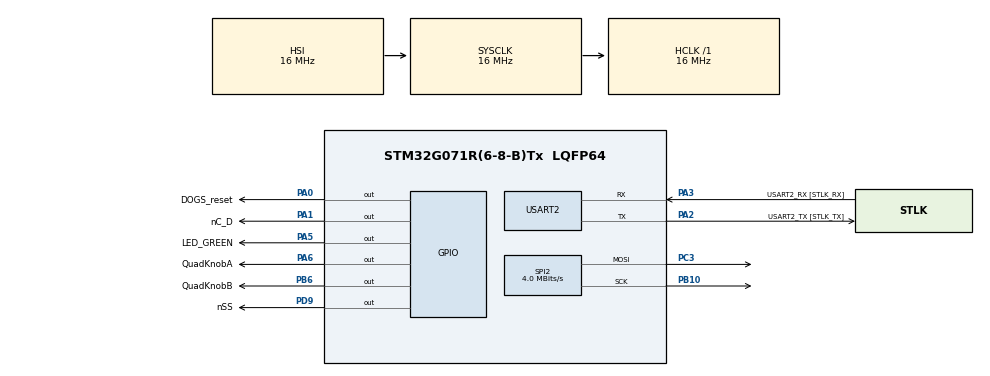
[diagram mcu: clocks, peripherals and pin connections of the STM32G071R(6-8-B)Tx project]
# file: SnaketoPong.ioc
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Mcu.Family=STM32G0
Mcu.Name=STM32G071R(6-8-B)Tx
Mcu.Package=LQFP64
NVIC.TIM17_IRQn=true\:0\:0\:false\:false\:true\:true\:true\:true
PA0.GPIO_Label=DOGS_reset
PA0.Signal=GPIO_Output
PA1.GPIO_Label=nC_D
PA1.Signal=GPIO_Output
PA13.GPIO_Label=TMS
PA13.Mode=Serial_Wire
PA13.Signal=SYS_SWDIO
PA14-BOOT0.GPIO_Label=TCK
PA14-BOOT0.Mode=Serial_Wire
PA14-BOOT0.Signal=SYS_SWCLK
PA2.GPIO_Label=USART2_TX [STLK_TX]
PA2.GPIO_PuPd=GPIO_PULLUP
PA2.Mode=Asynchronous
PA2.Signal=USART2_TX
PA3.GPIO_Label=USART2_RX [STLK_RX]
PA3.GPIO_PuPd=GPIO_PULLUP
PA3.Mode=Asynchronous
PA3.Signal=USART2_RX
PA5.GPIO_Label=LED_GREEN
PA5.GPIO_Speed=GPIO_SPEED_FREQ_HIGH
PA5.Signal=GPIO_Output
PA6.GPIO_Label=QuadKnobA
PA6.Signal=GPIO_Output
PB10.Mode=TX_Only_Simplex_Unidirect_Master
PB10.Signal=SPI2_SCK
PB6.GPIO_Label=QuadKnobB
PB6.Signal=GPIO_Output
PC13.Mode=SYS_WakeUp1
PC13.Signal=SYS_WKUP2
PC14-OSC32_IN\ (PC14).Mode=LSE-External-Oscillator
PC14-OSC32_IN\ (PC14).Signal=RCC_OSC32_IN
PC15-OSC32_OUT\ (PC15).Mode=LSE-External-Oscillator
PC15-OSC32_OUT\ (PC15).Signal=RCC_OSC32_OUT
PC3.Mode=TX_Only_Simplex_Unidirect_Master
PC3.Signal=SPI2_MOSI
PD9.GPIO_Label=nSS
PD9.Signal=GPIO_Output
PF0-OSC_IN\ (PF0).GPIO_Label=MCO
PF0-OSC_IN\ (PF0).Mode=HSE-External-Clock-Source
PF0-OSC_IN\ (PF0).Signal=RCC_OSC_IN
ProjectManager.HeapSize=0x200
ProjectManager.StackSize=0x400
ProjectManager.TargetToolchain=STM32CubeIDE
RCC.AHBFreq_Value=16000000
RCC.CortexFreq_Value=16000000
RCC.EXTERNAL_CLOCK_VALUE=12288000
RCC.HCLKFreq_Value=16000000
RCC.HSE_VALUE=8000000
RCC.HSI_VALUE=16000000
RCC.SYSCLKFreq_VALUE=16000000
RCC.VCOOutputFreq_Value=128000000
SPI2.BaudRatePrescaler=SPI_BAUDRATEPRESCALER_4
SPI2.CalculateBaudRate=4.0 MBits/s
SPI2.DataSize=SPI_DATASIZE_8BIT
SPI2.Direction=SPI_DIRECTION_2LINES
SPI2.Mode=SPI_MODE_MASTER
SPI2.VirtualType=VM_MASTER
TIM17.AutoReloadPreload=TIM_AUTORELOAD_PRELOAD_DISABLE
TIM17.Period=16000
TIM17.Prescaler=1
USART2.VirtualMode-Asynchronous=VM_ASYNC
VP_TIM17_VS_ClockSourceINT.Mode=Enable_Timer
board=NUCLEO-G071RB

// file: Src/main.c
/* USER CODE BEGIN Header */
/**
  ******************************************************************************
  * @file           : main.c
  * @brief          : Main program body
  ******************************************************************************
  * @attention
  *
  * Copyright (c) 2022 STMicroelectronics.
  * All rights reserved.
  *
  * This software is licensed under terms that can be found in the LICENSE file
  * in the root directory of this software component.
  * If no LICENSE file comes with this software, it is provided AS-IS.
  *
  ******************************************************************************
  */
/* USER CODE END Header */
#include "main.h"

/* USER CODE BEGIN Includes */
#include <stdint.h>
#include "smc_queue.h"
#include "snake_main.h"
/* USER CODE END Includes */

SPI_HandleTypeDef hspi2;

TIM_HandleTypeDef htim17;

UART_HandleTypeDef huart2;

/* USER CODE BEGIN PV */
 SPI_HandleTypeDef hspi2;
/* USER CODE END PV */

void SystemClock_Config(void);
static void MX_GPIO_Init(void);
static void MX_USART2_UART_Init(void);
static void MX_SPI2_Init(void);
static void MX_TIM17_Init(void);

/* USER CODE BEGIN 0 */

// Timer 17 running at 10 ms period will
volatile int32_t timer_isr_countdown = 10000;
void HAL_TIM_PeriodElapsedCallback(TIM_HandleTypeDef *htim){
	timer_isr_countdown--;
}
/* USER CODE END 0 */

int main(void)
{

  /* MCU Configuration--------------------------------------------------------*/

  /* Reset of all peripherals, Initializes the Flash interface and the Systick. */
  HAL_Init();

  /* Configure the system clock */
  SystemClock_Config();

  /* Initialize all configured peripherals */
  MX_GPIO_Init();
  MX_USART2_UART_Init();
  MX_SPI2_Init();
  MX_TIM17_Init();
  /* USER CODE BEGIN 2 */

  HAL_TIM_Base_Start_IT(&htim17);  // SMC - Start the timer
  pong_main();

  /* USER CODE END 2 */

  /* Infinite loop */
  while (1)
  {

  }
}

void SystemClock_Config(void)
{
  RCC_OscInitTypeDef RCC_OscInitStruct = {0};
  RCC_ClkInitTypeDef RCC_ClkInitStruct = {0};

  /** Configure the main internal regulator output voltage
  */
  HAL_PWREx_ControlVoltageScaling(PWR_REGULATOR_VOLTAGE_SCALE1);

  /** Initializes the RCC Oscillators according to the specified parameters
  * in the RCC_OscInitTypeDef structure.
  */
  RCC_OscInitStruct.OscillatorType = RCC_OSCILLATORTYPE_HSI;
  RCC_OscInitStruct.HSIState = RCC_HSI_ON;
  RCC_OscInitStruct.HSIDiv = RCC_HSI_DIV1;
  RCC_OscInitStruct.HSICalibrationValue = RCC_HSICALIBRATION_DEFAULT;
  RCC_OscInitStruct.PLL.PLLState = RCC_PLL_NONE;
  if (HAL_RCC_OscConfig(&RCC_OscInitStruct) != HAL_OK)
  {
    Error_Handler();
  }

  /** Initializes the CPU, AHB and APB buses clocks
  */
  RCC_ClkInitStruct.ClockType = RCC_CLOCKTYPE_HCLK|RCC_CLOCKTYPE_SYSCLK
                              |RCC_CLOCKTYPE_PCLK1;
  RCC_ClkInitStruct.SYSCLKSource = RCC_SYSCLKSOURCE_HSI;
  RCC_ClkInitStruct.AHBCLKDivider = RCC_SYSCLK_DIV1;
  RCC_ClkInitStruct.APB1CLKDivider = RCC_HCLK_DIV1;

  if (HAL_RCC_ClockConfig(&RCC_ClkInitStruct, FLASH_LATENCY_0) != HAL_OK)
  {
    Error_Handler();
  }
}

static void MX_SPI2_Init(void)
{

  /* SPI2 parameter configuration*/
  hspi2.Instance = SPI2;
  hspi2.Init.Mode = SPI_MODE_MASTER;
  hspi2.Init.Direction = SPI_DIRECTION_2LINES;
  hspi2.Init.DataSize = SPI_DATASIZE_8BIT;
  hspi2.Init.CLKPolarity = SPI_POLARITY_LOW;
  hspi2.Init.CLKPhase = SPI_PHASE_1EDGE;
  hspi2.Init.NSS = SPI_NSS_SOFT;
  hspi2.Init.BaudRatePrescaler = SPI_BAUDRATEPRESCALER_4;
  hspi2.Init.FirstBit = SPI_FIRSTBIT_MSB;
  hspi2.Init.TIMode = SPI_TIMODE_DISABLE;
  hspi2.Init.CRCCalculation = SPI_CRCCALCULATION_DISABLE;
  hspi2.Init.CRCPolynomial = 7;
  hspi2.Init.CRCLength = SPI_CRC_LENGTH_DATASIZE;
  hspi2.Init.NSSPMode = SPI_NSS_PULSE_ENABLE;
  if (HAL_SPI_Init(&hspi2) != HAL_OK)
  {
    Error_Handler();
  }

}

static void MX_TIM17_Init(void)
{

  htim17.Instance = TIM17;
  htim17.Init.Prescaler = 0;
  htim17.Init.CounterMode = TIM_COUNTERMODE_UP;
  htim17.Init.Period = 32000;
  htim17.Init.ClockDivision = TIM_CLOCKDIVISION_DIV1;
  htim17.Init.RepetitionCounter = 0;
  htim17.Init.AutoReloadPreload = TIM_AUTORELOAD_PRELOAD_DISABLE;
  if (HAL_TIM_Base_Init(&htim17) != HAL_OK)
  {
    Error_Handler();
  }

}

static void MX_USART2_UART_Init(void)
{

  huart2.Instance = USART2;
  huart2.Init.BaudRate = 115200;
  huart2.Init.WordLength = UART_WORDLENGTH_8B;
  huart2.Init.StopBits = UART_STOPBITS_1;
  huart2.Init.Parity = UART_PARITY_NONE;
  huart2.Init.Mode = UART_MODE_TX_RX;
  huart2.Init.HwFlowCtl = UART_HWCONTROL_NONE;
  huart2.Init.OverSampling = UART_OVERSAMPLING_16;
  huart2.Init.OneBitSampling = UART_ONE_BIT_SAMPLE_DISABLE;
  huart2.Init.ClockPrescaler = UART_PRESCALER_DIV1;
  huart2.AdvancedInit.AdvFeatureInit = UART_ADVFEATURE_NO_INIT;
  if (HAL_UART_Init(&huart2) != HAL_OK)
  {
    Error_Handler();
  }
  if (HAL_UARTEx_SetTxFifoThreshold(&huart2, UART_TXFIFO_THRESHOLD_1_8) != HAL_OK)
  {
    Error_Handler();
  }
  if (HAL_UARTEx_SetRxFifoThreshold(&huart2, UART_RXFIFO_THRESHOLD_1_8) != HAL_OK)
  {
    Error_Handler();
  }
  if (HAL_UARTEx_DisableFifoMode(&huart2) != HAL_OK)
  {
    Error_Handler();
  }

}

static void MX_GPIO_Init(void)
{
  GPIO_InitTypeDef GPIO_InitStruct = {0};

  /* GPIO Ports Clock Enable */
  __HAL_RCC_GPIOC_CLK_ENABLE();
  __HAL_RCC_GPIOF_CLK_ENABLE();
  __HAL_RCC_GPIOA_CLK_ENABLE();
  __HAL_RCC_GPIOB_CLK_ENABLE();
  __HAL_RCC_GPIOD_CLK_ENABLE();

  /*Configure GPIO pin Output Level */
  HAL_GPIO_WritePin(GPIOA, GPIO_PIN_0|GPIO_PIN_1|LED_GREEN_Pin, GPIO_PIN_RESET);

  /*Configure GPIO pin Output Level */
  HAL_GPIO_WritePin(GPIOD, GPIO_PIN_9, GPIO_PIN_RESET);

  /*Configure GPIO pins : PA0 PA1 */
  GPIO_InitStruct.Pin = GPIO_PIN_0|GPIO_PIN_1;
  GPIO_InitStruct.Mode = GPIO_MODE_OUTPUT_PP;
  GPIO_InitStruct.Pull = GPIO_NOPULL;
  GPIO_InitStruct.Speed = GPIO_SPEED_FREQ_LOW;
  HAL_GPIO_Init(GPIOA, &GPIO_InitStruct);

  /*Configure GPIO pin : LED_GREEN_Pin */
  GPIO_InitStruct.Pin = LED_GREEN_Pin;
  GPIO_InitStruct.Mode = GPIO_MODE_OUTPUT_PP;
  GPIO_InitStruct.Pull = GPIO_NOPULL;
  GPIO_InitStruct.Speed = GPIO_SPEED_FREQ_HIGH;
  HAL_GPIO_Init(LED_GREEN_GPIO_Port, &GPIO_InitStruct);

  /*Configure GPIO pins : PB0 PB1 PB2 PB3 */
  GPIO_InitStruct.Pin = GPIO_PIN_0|GPIO_PIN_1|GPIO_PIN_2|GPIO_PIN_3;
  GPIO_InitStruct.Mode = GPIO_MODE_INPUT;
  GPIO_InitStruct.Pull = GPIO_NOPULL;
  HAL_GPIO_Init(GPIOB, &GPIO_InitStruct);

  /*Configure GPIO pin : PD9 */
  GPIO_InitStruct.Pin = GPIO_PIN_9;
  GPIO_InitStruct.Mode = GPIO_MODE_OUTPUT_PP;
  GPIO_InitStruct.Pull = GPIO_NOPULL;
  GPIO_InitStruct.Speed = GPIO_SPEED_FREQ_LOW;
  HAL_GPIO_Init(GPIOD, &GPIO_InitStruct);

}

void Error_Handler(void)
{
  __disable_irq();
  while (1)
  {
  }
}
